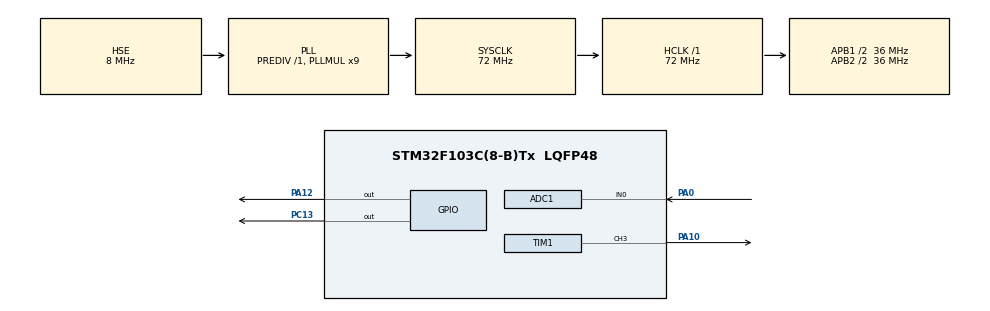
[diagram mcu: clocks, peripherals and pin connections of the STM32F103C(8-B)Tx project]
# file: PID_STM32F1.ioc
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ADC1.Channel-0\#ChannelRegularConversion=ADC_CHANNEL_0
ADC1.ContinuousConvMode=ENABLE
ADC1.NbrOfConversion=1
ADC1.NbrOfConversionFlag=1
ADC1.Rank-0\#ChannelRegularConversion=1
ADC1.SamplingTime-0\#ChannelRegularConversion=ADC_SAMPLETIME_7CYCLES_5
ADC1.master=1
Mcu.Family=STM32F1
Mcu.Name=STM32F103C(8-B)Tx
Mcu.Package=LQFP48
NVIC.PriorityGroup=NVIC_PRIORITYGROUP_4
NVIC.TIM2_IRQn=true\:0\:0\:false\:false\:true\:true
PA0-WKUP.Signal=ADCx_IN0
PA10.Signal=S_TIM1_CH3
PA12.Signal=GPIO_Output
PA13.Mode=Serial_Wire
PA13.Signal=SYS_JTMS-SWDIO
PA14.Mode=Serial_Wire
PA14.Signal=SYS_JTCK-SWCLK
PC13-TAMPER-RTC.Signal=GPIO_Output
PD0-OSC_IN.Mode=HSE-External-Oscillator
PD0-OSC_IN.Signal=RCC_OSC_IN
PD1-OSC_OUT.Mode=HSE-External-Oscillator
PD1-OSC_OUT.Signal=RCC_OSC_OUT
ProjectManager.HeapSize=0x200
ProjectManager.StackSize=0x400
ProjectManager.TargetToolchain=SW4STM32
RCC.ADCPresc=RCC_ADCPCLK2_DIV8
RCC.AHBFreq_Value=72000000
RCC.APB1CLKDivider=RCC_HCLK_DIV2
RCC.APB1Freq_Value=36000000
RCC.APB1TimFreq_Value=72000000
RCC.APB2CLKDivider=RCC_HCLK_DIV2
RCC.APB2Freq_Value=36000000
RCC.APB2TimFreq_Value=72000000
RCC.HCLKFreq_Value=72000000
RCC.PLLMUL=RCC_PLL_MUL9
RCC.PLLSourceVirtual=RCC_PLLSOURCE_HSE
RCC.SYSCLKFreq_VALUE=72000000
RCC.SYSCLKSource=RCC_SYSCLKSOURCE_PLLCLK
RCC.USBFreq_Value=72000000
SH.ADCx_IN0.0=ADC1_IN0,IN0
SH.S_TIM1_CH3.0=TIM1_CH3,PWM Generation3 CH3
TIM1.Channel-PWM\ Generation3\ CH3=TIM_CHANNEL_3
TIM1.Period=3199
TIM2.Period=3199
TIM2.Prescaler=0
VP_TIM1_VS_ClockSourceINT.Mode=Internal
VP_TIM2_VS_ClockSourceINT.Mode=Internal
board=custom

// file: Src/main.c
/* USER CODE BEGIN Header */
/**
  ******************************************************************************
  * @file           : main.c
  * @brief          : Main program body
  ******************************************************************************
  ** This notice applies to any and all portions of this file
  * that are not between comment pairs USER CODE BEGIN and
  * USER CODE END. Other portions of this file, whether
  * inserted by the user or by software development tools
  * are owned by their respective copyright owners.
  *
  * COPYRIGHT(c) 2019 STMicroelectronics
  *
  * Redistribution and use in source and binary forms, with or without modification,
  * are permitted provided that the following conditions are met:
  *   1. Redistributions of source code must retain the above copyright notice,
  *      this list of conditions and the following disclaimer.
  *   2. Redistributions in binary form must reproduce the above copyright notice,
  *      this list of conditions and the following disclaimer in the documentation
  *      and/or other materials provided with the distribution.
  *   3. Neither the name of STMicroelectronics nor the names of its contributors
  *      may be used to endorse or promote products derived from this software
  *      without specific prior written permission.
  *
  * THIS SOFTWARE IS PROVIDED BY THE COPYRIGHT HOLDERS AND CONTRIBUTORS "AS IS"
  * AND ANY EXPRESS OR IMPLIED WARRANTIES, INCLUDING, BUT NOT LIMITED TO, THE
  * IMPLIED WARRANTIES OF MERCHANTABILITY AND FITNESS FOR A PARTICULAR PURPOSE ARE
  * DISCLAIMED. IN NO EVENT SHALL THE COPYRIGHT HOLDER OR CONTRIBUTORS BE LIABLE
  * FOR ANY DIRECT, INDIRECT, INCIDENTAL, SPECIAL, EXEMPLARY, OR CONSEQUENTIAL
  * DAMAGES (INCLUDING, BUT NOT LIMITED TO, PROCUREMENT OF SUBSTITUTE GOODS OR
  * SERVICES; LOSS OF USE, DATA, OR PROFITS; OR BUSINESS INTERRUPTION) HOWEVER
  * CAUSED AND ON ANY THEORY OF LIABILITY, WHETHER IN CONTRACT, STRICT LIABILITY,
  * OR TORT (INCLUDING NEGLIGENCE OR OTHERWISE) ARISING IN ANY WAY OUT OF THE USE
  * OF THIS SOFTWARE, EVEN IF ADVISED OF THE POSSIBILITY OF SUCH DAMAGE.
  *
  ******************************************************************************
  */
/* USER CODE END Header */

#include <portMCU.h>
#include "main.h"

/* USER CODE BEGIN Includes */
#include <string.h>
#include "pidlib.h"
/* USER CODE END Includes */

/* USER CODE BEGIN PD */
#define K	(COUNTER_PERIOD - 1) * 3.3 / ADC_RANGE

/* USER CODE END PD */

/* USER CODE BEGIN PM */

#ifdef RAM_RUN

typedef void (*pid_func_type)(pid_type*);
unsigned int alloc[128], alloc_rti[16];
pid_func_type pidLoopRoutine_ram, pidInterruptRoutine_ram;

#define RAM_CPY(FUNC_RAM, FUNC, ALLOC)	({	\
									memcpy((void *)ALLOC, (void *)((signed int)FUNC & ~1), sizeof(ALLOC));\
									FUNC_RAM = (pid_func_type)((unsigned int)ALLOC | 1);			\
								})

#define PID_INTERRUPT_ROUTINE(__PID__) pidInterruptRoutine_ram(__PID__)
#define PID_LOOP_ROUTINE(__PID__) pidLoopRoutine_ram(__PID__)

#else
#define PID_INTERRUPT_ROUTINE(__PID__) pidInterruptRoutine(__PID__)
#define PID_LOOP_ROUTINE(__PID__) pidLoopRoutine(__PID__)
#endif

/* USER CODE END PM */

ADC_HandleTypeDef hadc1;

TIM_HandleTypeDef htim1;
TIM_HandleTypeDef htim2;

/* USER CODE BEGIN PV */
pid_type pid;
/* USER CODE END PV */

void SystemClock_Config(void);
static void MX_GPIO_Init(void);
static void MX_ADC1_Init(void);
static void MX_TIM1_Init(void);
static void MX_TIM2_Init(void);

/* USER CODE BEGIN 0 */
void HAL_TIM_PeriodElapsedCallback(TIM_HandleTypeDef *htim){
	if(htim->Instance==TIM2){
		PID_INTERRUPT_ROUTINE(&pid);
	}
}
/* USER CODE END 0 */

int main(void)
{

  /* MCU Configuration--------------------------------------------------------*/

  /* Reset of all peripherals, Initializes the Flash interface and the Systick. */
  HAL_Init();

  /* USER CODE BEGIN Init */
#ifdef RAM_RUN
  RAM_CPY(pidInterruptRoutine_ram, pidInterruptRoutine, alloc_rti);
  RAM_CPY(pidLoopRoutine_ram, pidLoopRoutine, alloc);
#endif

  new_PID(&pid, PARSE_OP(0.55 * K), PARSE_OP(-0.8 * K), (int)PARSE_OP(0.35 * K), ADC_RANGE * 0.303, DUTY_RES * 0.01, DUTY_RES * 0.99);
  /* USER CODE END Init */

  /* Configure the system clock */
  SystemClock_Config();

  /* Initialize all configured peripherals */
  MX_GPIO_Init();
  MX_ADC1_Init();
  MX_TIM1_Init();
  MX_TIM2_Init();
  /* USER CODE BEGIN 2 */
  HAL_TIM_Base_Start_IT(&htim2);
  HAL_TIM_PWM_Start(&htim1,TIM_CHANNEL_3);
  HAL_ADC_Start(&hadc1);
  /* USER CODE END 2 */

  /* Infinite loop */
  while (1)
  {

    /* USER CODE BEGIN 3 */
	  PID_LOOP_ROUTINE(&pid);
  }
  /* USER CODE END 3 */
}

void SystemClock_Config(void)
{
  RCC_OscInitTypeDef RCC_OscInitStruct = {0};
  RCC_ClkInitTypeDef RCC_ClkInitStruct = {0};
  RCC_PeriphCLKInitTypeDef PeriphClkInit = {0};

  /**Initializes the CPU, AHB and APB busses clocks
  */
  RCC_OscInitStruct.OscillatorType = RCC_OSCILLATORTYPE_HSE;
  RCC_OscInitStruct.HSEState = RCC_HSE_ON;
  RCC_OscInitStruct.HSEPredivValue = RCC_HSE_PREDIV_DIV1;
  RCC_OscInitStruct.HSIState = RCC_HSI_ON;
  RCC_OscInitStruct.PLL.PLLState = RCC_PLL_ON;
  RCC_OscInitStruct.PLL.PLLSource = RCC_PLLSOURCE_HSE;
  RCC_OscInitStruct.PLL.PLLMUL = RCC_PLL_MUL9;
  if (HAL_RCC_OscConfig(&RCC_OscInitStruct) != HAL_OK)
  {
    Error_Handler();
  }
  /**Initializes the CPU, AHB and APB busses clocks
  */
  RCC_ClkInitStruct.ClockType = RCC_CLOCKTYPE_HCLK|RCC_CLOCKTYPE_SYSCLK
                              |RCC_CLOCKTYPE_PCLK1|RCC_CLOCKTYPE_PCLK2;
  RCC_ClkInitStruct.SYSCLKSource = RCC_SYSCLKSOURCE_PLLCLK;
  RCC_ClkInitStruct.AHBCLKDivider = RCC_SYSCLK_DIV1;
  RCC_ClkInitStruct.APB1CLKDivider = RCC_HCLK_DIV2;
  RCC_ClkInitStruct.APB2CLKDivider = RCC_HCLK_DIV2;

  if (HAL_RCC_ClockConfig(&RCC_ClkInitStruct, FLASH_LATENCY_2) != HAL_OK)
  {
    Error_Handler();
  }
  PeriphClkInit.PeriphClockSelection = RCC_PERIPHCLK_ADC;
  PeriphClkInit.AdcClockSelection = RCC_ADCPCLK2_DIV8;
  if (HAL_RCCEx_PeriphCLKConfig(&PeriphClkInit) != HAL_OK)
  {
    Error_Handler();
  }
}

static void MX_ADC1_Init(void)
{

  ADC_ChannelConfTypeDef sConfig = {0};

  /**Common config
  */
  hadc1.Instance = ADC1;
  hadc1.Init.ScanConvMode = ADC_SCAN_DISABLE;
  hadc1.Init.ContinuousConvMode = ENABLE;
  hadc1.Init.DiscontinuousConvMode = DISABLE;
  hadc1.Init.ExternalTrigConv = ADC_SOFTWARE_START;
  hadc1.Init.DataAlign = ADC_DATAALIGN_RIGHT;
  hadc1.Init.NbrOfConversion = 1;
  if (HAL_ADC_Init(&hadc1) != HAL_OK)
  {
    Error_Handler();
  }
  /**Configure Regular Channel
  */
  sConfig.Channel = ADC_CHANNEL_0;
  sConfig.Rank = ADC_REGULAR_RANK_1;
  sConfig.SamplingTime = ADC_SAMPLETIME_7CYCLES_5;
  if (HAL_ADC_ConfigChannel(&hadc1, &sConfig) != HAL_OK)
  {
    Error_Handler();
  }

}

static void MX_TIM1_Init(void)
{

  TIM_ClockConfigTypeDef sClockSourceConfig = {0};
  TIM_MasterConfigTypeDef sMasterConfig = {0};
  TIM_OC_InitTypeDef sConfigOC = {0};
  TIM_BreakDeadTimeConfigTypeDef sBreakDeadTimeConfig = {0};

  htim1.Instance = TIM1;
  htim1.Init.Prescaler = 10;
  htim1.Init.CounterMode = TIM_COUNTERMODE_UP;
  htim1.Init.Period = 3599;
  htim1.Init.ClockDivision = TIM_CLOCKDIVISION_DIV1;
  htim1.Init.RepetitionCounter = 0;
  htim1.Init.AutoReloadPreload = TIM_AUTORELOAD_PRELOAD_DISABLE;
  if (HAL_TIM_Base_Init(&htim1) != HAL_OK)
  {
    Error_Handler();
  }
  sClockSourceConfig.ClockSource = TIM_CLOCKSOURCE_INTERNAL;
  if (HAL_TIM_ConfigClockSource(&htim1, &sClockSourceConfig) != HAL_OK)
  {
    Error_Handler();
  }
  if (HAL_TIM_PWM_Init(&htim1) != HAL_OK)
  {
    Error_Handler();
  }
  sMasterConfig.MasterOutputTrigger = TIM_TRGO_RESET;
  sMasterConfig.MasterSlaveMode = TIM_MASTERSLAVEMODE_DISABLE;
  if (HAL_TIMEx_MasterConfigSynchronization(&htim1, &sMasterConfig) != HAL_OK)
  {
    Error_Handler();
  }
  sConfigOC.OCMode = TIM_OCMODE_PWM1;
  sConfigOC.Pulse = 0;
  sConfigOC.OCPolarity = TIM_OCPOLARITY_HIGH;
  sConfigOC.OCNPolarity = TIM_OCNPOLARITY_HIGH;
  sConfigOC.OCFastMode = TIM_OCFAST_DISABLE;
  sConfigOC.OCIdleState = TIM_OCIDLESTATE_RESET;
  sConfigOC.OCNIdleState = TIM_OCNIDLESTATE_RESET;
  if (HAL_TIM_PWM_ConfigChannel(&htim1, &sConfigOC, TIM_CHANNEL_3) != HAL_OK)
  {
    Error_Handler();
  }
  sBreakDeadTimeConfig.OffStateRunMode = TIM_OSSR_DISABLE;
  sBreakDeadTimeConfig.OffStateIDLEMode = TIM_OSSI_DISABLE;
  sBreakDeadTimeConfig.LockLevel = TIM_LOCKLEVEL_OFF;
  sBreakDeadTimeConfig.DeadTime = 0;
  sBreakDeadTimeConfig.BreakState = TIM_BREAK_DISABLE;
  sBreakDeadTimeConfig.BreakPolarity = TIM_BREAKPOLARITY_HIGH;
  sBreakDeadTimeConfig.AutomaticOutput = TIM_AUTOMATICOUTPUT_DISABLE;
  if (HAL_TIMEx_ConfigBreakDeadTime(&htim1, &sBreakDeadTimeConfig) != HAL_OK)
  {
    Error_Handler();
  }
  HAL_TIM_MspPostInit(&htim1);

}

static void MX_TIM2_Init(void)
{

  TIM_ClockConfigTypeDef sClockSourceConfig = {0};
  TIM_MasterConfigTypeDef sMasterConfig = {0};

  htim2.Instance = TIM2;
  htim2.Init.Prescaler = 10;
  htim2.Init.CounterMode = TIM_COUNTERMODE_UP;
  htim2.Init.Period = 3599;
  htim2.Init.ClockDivision = TIM_CLOCKDIVISION_DIV1;
  htim2.Init.AutoReloadPreload = TIM_AUTORELOAD_PRELOAD_DISABLE;
  if (HAL_TIM_Base_Init(&htim2) != HAL_OK)
  {
    Error_Handler();
  }
  sClockSourceConfig.ClockSource = TIM_CLOCKSOURCE_INTERNAL;
  if (HAL_TIM_ConfigClockSource(&htim2, &sClockSourceConfig) != HAL_OK)
  {
    Error_Handler();
  }
  sMasterConfig.MasterOutputTrigger = TIM_TRGO_RESET;
  sMasterConfig.MasterSlaveMode = TIM_MASTERSLAVEMODE_DISABLE;
  if (HAL_TIMEx_MasterConfigSynchronization(&htim2, &sMasterConfig) != HAL_OK)
  {
    Error_Handler();
  }

}

static void MX_GPIO_Init(void)
{
  GPIO_InitTypeDef GPIO_InitStruct = {0};

  /* GPIO Ports Clock Enable */
  __HAL_RCC_GPIOC_CLK_ENABLE();
  __HAL_RCC_GPIOD_CLK_ENABLE();
  __HAL_RCC_GPIOA_CLK_ENABLE();

  /*Configure GPIO pin Output Level */
  HAL_GPIO_WritePin(GPIOA, GPIO_PIN_8 | GPIO_PIN_9, GPIO_PIN_RESET);

  /*Configure GPIO pin : PA12 */
  GPIO_InitStruct.Pin = GPIO_PIN_8 | GPIO_PIN_9;
  GPIO_InitStruct.Mode = GPIO_MODE_OUTPUT_PP;
  GPIO_InitStruct.Pull = GPIO_NOPULL;
  GPIO_InitStruct.Speed = GPIO_SPEED_FREQ_LOW;
  HAL_GPIO_Init(GPIOA, &GPIO_InitStruct);

}

void Error_Handler(void)
{
}

/************************ (C) COPYRIGHT STMicroelectronics *****END OF FILE****/
